VERSION 5.7 ;
BUSBITCHARS "[]" ;
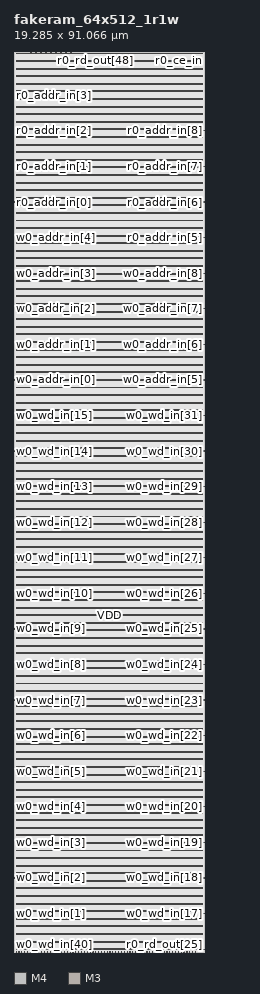
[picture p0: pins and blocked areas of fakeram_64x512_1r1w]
MACRO fakeram_64x512_1r1w
  FOREIGN fakeram_64x512_1r1w 0 0 ;
  SYMMETRY X Y R90 ;
  SIZE 19.285 BY 91.066 ;
  CLASS BLOCK ;
  PIN w0_wd_in[0]
    DIRECTION INPUT ;
    USE SIGNAL ;
    SHAPE ABUTMENT ;
    PORT
      LAYER M4 ;
      RECT 0.000 0.276 0.072 0.300 ;
    END
  END w0_wd_in[0]
  PIN w0_wd_in[1]
    DIRECTION INPUT ;
    USE SIGNAL ;
    SHAPE ABUTMENT ;
    PORT
      LAYER M4 ;
      RECT 0.000 3.876 0.072 3.900 ;
    END
  END w0_wd_in[1]
  PIN w0_wd_in[2]
    DIRECTION INPUT ;
    USE SIGNAL ;
    SHAPE ABUTMENT ;
    PORT
      LAYER M4 ;
      RECT 0.000 7.476 0.072 7.500 ;
    END
  END w0_wd_in[2]
  PIN w0_wd_in[3]
    DIRECTION INPUT ;
    USE SIGNAL ;
    SHAPE ABUTMENT ;
    PORT
      LAYER M4 ;
      RECT 0.000 11.076 0.072 11.100 ;
    END
  END w0_wd_in[3]
  PIN w0_wd_in[4]
    DIRECTION INPUT ;
    USE SIGNAL ;
    SHAPE ABUTMENT ;
    PORT
      LAYER M4 ;
      RECT 0.000 14.676 0.072 14.700 ;
    END
  END w0_wd_in[4]
  PIN w0_wd_in[5]
    DIRECTION INPUT ;
    USE SIGNAL ;
    SHAPE ABUTMENT ;
    PORT
      LAYER M4 ;
      RECT 0.000 18.276 0.072 18.300 ;
    END
  END w0_wd_in[5]
  PIN w0_wd_in[6]
    DIRECTION INPUT ;
    USE SIGNAL ;
    SHAPE ABUTMENT ;
    PORT
      LAYER M4 ;
      RECT 0.000 21.876 0.072 21.900 ;
    END
  END w0_wd_in[6]
  PIN w0_wd_in[7]
    DIRECTION INPUT ;
    USE SIGNAL ;
    SHAPE ABUTMENT ;
    PORT
      LAYER M4 ;
      RECT 0.000 25.476 0.072 25.500 ;
    END
  END w0_wd_in[7]
  PIN w0_wd_in[8]
    DIRECTION INPUT ;
    USE SIGNAL ;
    SHAPE ABUTMENT ;
    PORT
      LAYER M4 ;
      RECT 0.000 29.076 0.072 29.100 ;
    END
  END w0_wd_in[8]
  PIN w0_wd_in[9]
    DIRECTION INPUT ;
    USE SIGNAL ;
    SHAPE ABUTMENT ;
    PORT
      LAYER M4 ;
      RECT 0.000 32.676 0.072 32.700 ;
    END
  END w0_wd_in[9]
  PIN w0_wd_in[10]
    DIRECTION INPUT ;
    USE SIGNAL ;
    SHAPE ABUTMENT ;
    PORT
      LAYER M4 ;
      RECT 0.000 36.276 0.072 36.300 ;
    END
  END w0_wd_in[10]
  PIN w0_wd_in[11]
    DIRECTION INPUT ;
    USE SIGNAL ;
    SHAPE ABUTMENT ;
    PORT
      LAYER M4 ;
      RECT 0.000 39.876 0.072 39.900 ;
    END
  END w0_wd_in[11]
  PIN w0_wd_in[12]
    DIRECTION INPUT ;
    USE SIGNAL ;
    SHAPE ABUTMENT ;
    PORT
      LAYER M4 ;
      RECT 0.000 43.476 0.072 43.500 ;
    END
  END w0_wd_in[12]
  PIN w0_wd_in[13]
    DIRECTION INPUT ;
    USE SIGNAL ;
    SHAPE ABUTMENT ;
    PORT
      LAYER M4 ;
      RECT 0.000 47.076 0.072 47.100 ;
    END
  END w0_wd_in[13]
  PIN w0_wd_in[14]
    DIRECTION INPUT ;
    USE SIGNAL ;
    SHAPE ABUTMENT ;
    PORT
      LAYER M4 ;
      RECT 0.000 50.676 0.072 50.700 ;
    END
  END w0_wd_in[14]
  PIN w0_wd_in[15]
    DIRECTION INPUT ;
    USE SIGNAL ;
    SHAPE ABUTMENT ;
    PORT
      LAYER M4 ;
      RECT 0.000 54.276 0.072 54.300 ;
    END
  END w0_wd_in[15]
  PIN w0_wd_in[16]
    DIRECTION INPUT ;
    USE SIGNAL ;
    SHAPE ABUTMENT ;
    PORT
      LAYER M4 ;
      RECT 19.213 0.276 19.285 0.300 ;
    END
  END w0_wd_in[16]
  PIN w0_wd_in[17]
    DIRECTION INPUT ;
    USE SIGNAL ;
    SHAPE ABUTMENT ;
    PORT
      LAYER M4 ;
      RECT 19.213 3.876 19.285 3.900 ;
    END
  END w0_wd_in[17]
  PIN w0_wd_in[18]
    DIRECTION INPUT ;
    USE SIGNAL ;
    SHAPE ABUTMENT ;
    PORT
      LAYER M4 ;
      RECT 19.213 7.476 19.285 7.500 ;
    END
  END w0_wd_in[18]
  PIN w0_wd_in[19]
    DIRECTION INPUT ;
    USE SIGNAL ;
    SHAPE ABUTMENT ;
    PORT
      LAYER M4 ;
      RECT 19.213 11.076 19.285 11.100 ;
    END
  END w0_wd_in[19]
  PIN w0_wd_in[20]
    DIRECTION INPUT ;
    USE SIGNAL ;
    SHAPE ABUTMENT ;
    PORT
      LAYER M4 ;
      RECT 19.213 14.676 19.285 14.700 ;
    END
  END w0_wd_in[20]
  PIN w0_wd_in[21]
    DIRECTION INPUT ;
    USE SIGNAL ;
    SHAPE ABUTMENT ;
    PORT
      LAYER M4 ;
      RECT 19.213 18.276 19.285 18.300 ;
    END
  END w0_wd_in[21]
  PIN w0_wd_in[22]
    DIRECTION INPUT ;
    USE SIGNAL ;
    SHAPE ABUTMENT ;
    PORT
      LAYER M4 ;
      RECT 19.213 21.876 19.285 21.900 ;
    END
  END w0_wd_in[22]
  PIN w0_wd_in[23]
    DIRECTION INPUT ;
    USE SIGNAL ;
    SHAPE ABUTMENT ;
    PORT
      LAYER M4 ;
      RECT 19.213 25.476 19.285 25.500 ;
    END
  END w0_wd_in[23]
  PIN w0_wd_in[24]
    DIRECTION INPUT ;
    USE SIGNAL ;
    SHAPE ABUTMENT ;
    PORT
      LAYER M4 ;
      RECT 19.213 29.076 19.285 29.100 ;
    END
  END w0_wd_in[24]
  PIN w0_wd_in[25]
    DIRECTION INPUT ;
    USE SIGNAL ;
    SHAPE ABUTMENT ;
    PORT
      LAYER M4 ;
      RECT 19.213 32.676 19.285 32.700 ;
    END
  END w0_wd_in[25]
  PIN w0_wd_in[26]
    DIRECTION INPUT ;
    USE SIGNAL ;
    SHAPE ABUTMENT ;
    PORT
      LAYER M4 ;
      RECT 19.213 36.276 19.285 36.300 ;
    END
  END w0_wd_in[26]
  PIN w0_wd_in[27]
    DIRECTION INPUT ;
    USE SIGNAL ;
    SHAPE ABUTMENT ;
    PORT
      LAYER M4 ;
      RECT 19.213 39.876 19.285 39.900 ;
    END
  END w0_wd_in[27]
  PIN w0_wd_in[28]
    DIRECTION INPUT ;
    USE SIGNAL ;
    SHAPE ABUTMENT ;
    PORT
      LAYER M4 ;
      RECT 19.213 43.476 19.285 43.500 ;
    END
  END w0_wd_in[28]
  PIN w0_wd_in[29]
    DIRECTION INPUT ;
    USE SIGNAL ;
    SHAPE ABUTMENT ;
    PORT
      LAYER M4 ;
      RECT 19.213 47.076 19.285 47.100 ;
    END
  END w0_wd_in[29]
  PIN w0_wd_in[30]
    DIRECTION INPUT ;
    USE SIGNAL ;
    SHAPE ABUTMENT ;
    PORT
      LAYER M4 ;
      RECT 19.213 50.676 19.285 50.700 ;
    END
  END w0_wd_in[30]
  PIN w0_wd_in[31]
    DIRECTION INPUT ;
    USE SIGNAL ;
    SHAPE ABUTMENT ;
    PORT
      LAYER M4 ;
      RECT 19.213 54.276 19.285 54.300 ;
    END
  END w0_wd_in[31]
  PIN w0_wd_in[32]
    DIRECTION OUTPUT ;
    USE SIGNAL ;
    SHAPE ABUTMENT ;
    PORT
      LAYER M3 ;
      RECT 0.207 0.000 0.225 0.054 ;
    END
  END w0_wd_in[32]
  PIN w0_wd_in[33]
    DIRECTION OUTPUT ;
    USE SIGNAL ;
    SHAPE ABUTMENT ;
    PORT
      LAYER M3 ;
      RECT 0.495 0.000 0.513 0.054 ;
    END
  END w0_wd_in[33]
  PIN w0_wd_in[34]
    DIRECTION OUTPUT ;
    USE SIGNAL ;
    SHAPE ABUTMENT ;
    PORT
      LAYER M3 ;
      RECT 0.783 0.000 0.801 0.054 ;
    END
  END w0_wd_in[34]
  PIN w0_wd_in[35]
    DIRECTION OUTPUT ;
    USE SIGNAL ;
    SHAPE ABUTMENT ;
    PORT
      LAYER M3 ;
      RECT 1.071 0.000 1.089 0.054 ;
    END
  END w0_wd_in[35]
  PIN w0_wd_in[36]
    DIRECTION OUTPUT ;
    USE SIGNAL ;
    SHAPE ABUTMENT ;
    PORT
      LAYER M3 ;
      RECT 1.359 0.000 1.377 0.054 ;
    END
  END w0_wd_in[36]
  PIN w0_wd_in[37]
    DIRECTION OUTPUT ;
    USE SIGNAL ;
    SHAPE ABUTMENT ;
    PORT
      LAYER M3 ;
      RECT 1.647 0.000 1.665 0.054 ;
    END
  END w0_wd_in[37]
  PIN w0_wd_in[38]
    DIRECTION OUTPUT ;
    USE SIGNAL ;
    SHAPE ABUTMENT ;
    PORT
      LAYER M3 ;
      RECT 1.935 0.000 1.953 0.054 ;
    END
  END w0_wd_in[38]
  PIN w0_wd_in[39]
    DIRECTION OUTPUT ;
    USE SIGNAL ;
    SHAPE ABUTMENT ;
    PORT
      LAYER M3 ;
      RECT 2.223 0.000 2.241 0.054 ;
    END
  END w0_wd_in[39]
  PIN w0_wd_in[40]
    DIRECTION OUTPUT ;
    USE SIGNAL ;
    SHAPE ABUTMENT ;
    PORT
      LAYER M3 ;
      RECT 2.511 0.000 2.529 0.054 ;
    END
  END w0_wd_in[40]
  PIN w0_wd_in[41]
    DIRECTION OUTPUT ;
    USE SIGNAL ;
    SHAPE ABUTMENT ;
    PORT
      LAYER M3 ;
      RECT 2.799 0.000 2.817 0.054 ;
    END
  END w0_wd_in[41]
  PIN w0_wd_in[42]
    DIRECTION OUTPUT ;
    USE SIGNAL ;
    SHAPE ABUTMENT ;
    PORT
      LAYER M3 ;
      RECT 3.087 0.000 3.105 0.054 ;
    END
  END w0_wd_in[42]
  PIN w0_wd_in[43]
    DIRECTION OUTPUT ;
    USE SIGNAL ;
    SHAPE ABUTMENT ;
    PORT
      LAYER M3 ;
      RECT 3.375 0.000 3.393 0.054 ;
    END
  END w0_wd_in[43]
  PIN w0_wd_in[44]
    DIRECTION OUTPUT ;
    USE SIGNAL ;
    SHAPE ABUTMENT ;
    PORT
      LAYER M3 ;
      RECT 3.663 0.000 3.681 0.054 ;
    END
  END w0_wd_in[44]
  PIN w0_wd_in[45]
    DIRECTION OUTPUT ;
    USE SIGNAL ;
    SHAPE ABUTMENT ;
    PORT
      LAYER M3 ;
      RECT 3.951 0.000 3.969 0.054 ;
    END
  END w0_wd_in[45]
  PIN w0_wd_in[46]
    DIRECTION OUTPUT ;
    USE SIGNAL ;
    SHAPE ABUTMENT ;
    PORT
      LAYER M3 ;
      RECT 4.239 0.000 4.257 0.054 ;
    END
  END w0_wd_in[46]
  PIN w0_wd_in[47]
    DIRECTION OUTPUT ;
    USE SIGNAL ;
    SHAPE ABUTMENT ;
    PORT
      LAYER M3 ;
      RECT 4.527 0.000 4.545 0.054 ;
    END
  END w0_wd_in[47]
  PIN w0_wd_in[48]
    DIRECTION OUTPUT ;
    USE SIGNAL ;
    SHAPE ABUTMENT ;
    PORT
      LAYER M3 ;
      RECT 4.815 0.000 4.833 0.054 ;
    END
  END w0_wd_in[48]
  PIN w0_wd_in[49]
    DIRECTION OUTPUT ;
    USE SIGNAL ;
    SHAPE ABUTMENT ;
    PORT
      LAYER M3 ;
      RECT 5.103 0.000 5.121 0.054 ;
    END
  END w0_wd_in[49]
  PIN w0_wd_in[50]
    DIRECTION OUTPUT ;
    USE SIGNAL ;
    SHAPE ABUTMENT ;
    PORT
      LAYER M3 ;
      RECT 5.391 0.000 5.409 0.054 ;
    END
  END w0_wd_in[50]
  PIN w0_wd_in[51]
    DIRECTION OUTPUT ;
    USE SIGNAL ;
    SHAPE ABUTMENT ;
    PORT
      LAYER M3 ;
      RECT 5.679 0.000 5.697 0.054 ;
    END
  END w0_wd_in[51]
  PIN w0_wd_in[52]
    DIRECTION OUTPUT ;
    USE SIGNAL ;
    SHAPE ABUTMENT ;
    PORT
      LAYER M3 ;
      RECT 5.967 0.000 5.985 0.054 ;
    END
  END w0_wd_in[52]
  PIN w0_wd_in[53]
    DIRECTION OUTPUT ;
    USE SIGNAL ;
    SHAPE ABUTMENT ;
    PORT
      LAYER M3 ;
      RECT 6.255 0.000 6.273 0.054 ;
    END
  END w0_wd_in[53]
  PIN w0_wd_in[54]
    DIRECTION OUTPUT ;
    USE SIGNAL ;
    SHAPE ABUTMENT ;
    PORT
      LAYER M3 ;
      RECT 6.543 0.000 6.561 0.054 ;
    END
  END w0_wd_in[54]
  PIN w0_wd_in[55]
    DIRECTION OUTPUT ;
    USE SIGNAL ;
    SHAPE ABUTMENT ;
    PORT
      LAYER M3 ;
      RECT 6.831 0.000 6.849 0.054 ;
    END
  END w0_wd_in[55]
  PIN w0_wd_in[56]
    DIRECTION OUTPUT ;
    USE SIGNAL ;
    SHAPE ABUTMENT ;
    PORT
      LAYER M3 ;
      RECT 7.119 0.000 7.137 0.054 ;
    END
  END w0_wd_in[56]
  PIN w0_wd_in[57]
    DIRECTION OUTPUT ;
    USE SIGNAL ;
    SHAPE ABUTMENT ;
    PORT
      LAYER M3 ;
      RECT 7.407 0.000 7.425 0.054 ;
    END
  END w0_wd_in[57]
  PIN w0_wd_in[58]
    DIRECTION OUTPUT ;
    USE SIGNAL ;
    SHAPE ABUTMENT ;
    PORT
      LAYER M3 ;
      RECT 7.695 0.000 7.713 0.054 ;
    END
  END w0_wd_in[58]
  PIN w0_wd_in[59]
    DIRECTION OUTPUT ;
    USE SIGNAL ;
    SHAPE ABUTMENT ;
    PORT
      LAYER M3 ;
      RECT 7.983 0.000 8.001 0.054 ;
    END
  END w0_wd_in[59]
  PIN w0_wd_in[60]
    DIRECTION OUTPUT ;
    USE SIGNAL ;
    SHAPE ABUTMENT ;
    PORT
      LAYER M3 ;
      RECT 8.271 0.000 8.289 0.054 ;
    END
  END w0_wd_in[60]
  PIN w0_wd_in[61]
    DIRECTION OUTPUT ;
    USE SIGNAL ;
    SHAPE ABUTMENT ;
    PORT
      LAYER M3 ;
      RECT 8.559 0.000 8.577 0.054 ;
    END
  END w0_wd_in[61]
  PIN w0_wd_in[62]
    DIRECTION OUTPUT ;
    USE SIGNAL ;
    SHAPE ABUTMENT ;
    PORT
      LAYER M3 ;
      RECT 8.847 0.000 8.865 0.054 ;
    END
  END w0_wd_in[62]
  PIN w0_wd_in[63]
    DIRECTION OUTPUT ;
    USE SIGNAL ;
    SHAPE ABUTMENT ;
    PORT
      LAYER M3 ;
      RECT 9.135 0.000 9.153 0.054 ;
    END
  END w0_wd_in[63]
  PIN r0_rd_out[0]
    DIRECTION OUTPUT ;
    USE SIGNAL ;
    SHAPE ABUTMENT ;
    PORT
      LAYER M3 ;
      RECT 9.423 0.000 9.441 0.054 ;
    END
  END r0_rd_out[0]
  PIN r0_rd_out[1]
    DIRECTION OUTPUT ;
    USE SIGNAL ;
    SHAPE ABUTMENT ;
    PORT
      LAYER M3 ;
      RECT 9.711 0.000 9.729 0.054 ;
    END
  END r0_rd_out[1]
  PIN r0_rd_out[2]
    DIRECTION OUTPUT ;
    USE SIGNAL ;
    SHAPE ABUTMENT ;
    PORT
      LAYER M3 ;
      RECT 9.999 0.000 10.017 0.054 ;
    END
  END r0_rd_out[2]
  PIN r0_rd_out[3]
    DIRECTION OUTPUT ;
    USE SIGNAL ;
    SHAPE ABUTMENT ;
    PORT
      LAYER M3 ;
      RECT 10.287 0.000 10.305 0.054 ;
    END
  END r0_rd_out[3]
  PIN r0_rd_out[4]
    DIRECTION OUTPUT ;
    USE SIGNAL ;
    SHAPE ABUTMENT ;
    PORT
      LAYER M3 ;
      RECT 10.575 0.000 10.593 0.054 ;
    END
  END r0_rd_out[4]
  PIN r0_rd_out[5]
    DIRECTION OUTPUT ;
    USE SIGNAL ;
    SHAPE ABUTMENT ;
    PORT
      LAYER M3 ;
      RECT 10.863 0.000 10.881 0.054 ;
    END
  END r0_rd_out[5]
  PIN r0_rd_out[6]
    DIRECTION OUTPUT ;
    USE SIGNAL ;
    SHAPE ABUTMENT ;
    PORT
      LAYER M3 ;
      RECT 11.151 0.000 11.169 0.054 ;
    END
  END r0_rd_out[6]
  PIN r0_rd_out[7]
    DIRECTION OUTPUT ;
    USE SIGNAL ;
    SHAPE ABUTMENT ;
    PORT
      LAYER M3 ;
      RECT 11.439 0.000 11.457 0.054 ;
    END
  END r0_rd_out[7]
  PIN r0_rd_out[8]
    DIRECTION OUTPUT ;
    USE SIGNAL ;
    SHAPE ABUTMENT ;
    PORT
      LAYER M3 ;
      RECT 11.727 0.000 11.745 0.054 ;
    END
  END r0_rd_out[8]
  PIN r0_rd_out[9]
    DIRECTION OUTPUT ;
    USE SIGNAL ;
    SHAPE ABUTMENT ;
    PORT
      LAYER M3 ;
      RECT 12.015 0.000 12.033 0.054 ;
    END
  END r0_rd_out[9]
  PIN r0_rd_out[10]
    DIRECTION OUTPUT ;
    USE SIGNAL ;
    SHAPE ABUTMENT ;
    PORT
      LAYER M3 ;
      RECT 12.303 0.000 12.321 0.054 ;
    END
  END r0_rd_out[10]
  PIN r0_rd_out[11]
    DIRECTION OUTPUT ;
    USE SIGNAL ;
    SHAPE ABUTMENT ;
    PORT
      LAYER M3 ;
      RECT 12.591 0.000 12.609 0.054 ;
    END
  END r0_rd_out[11]
  PIN r0_rd_out[12]
    DIRECTION OUTPUT ;
    USE SIGNAL ;
    SHAPE ABUTMENT ;
    PORT
      LAYER M3 ;
      RECT 12.879 0.000 12.897 0.054 ;
    END
  END r0_rd_out[12]
  PIN r0_rd_out[13]
    DIRECTION OUTPUT ;
    USE SIGNAL ;
    SHAPE ABUTMENT ;
    PORT
      LAYER M3 ;
      RECT 13.167 0.000 13.185 0.054 ;
    END
  END r0_rd_out[13]
  PIN r0_rd_out[14]
    DIRECTION OUTPUT ;
    USE SIGNAL ;
    SHAPE ABUTMENT ;
    PORT
      LAYER M3 ;
      RECT 13.455 0.000 13.473 0.054 ;
    END
  END r0_rd_out[14]
  PIN r0_rd_out[15]
    DIRECTION OUTPUT ;
    USE SIGNAL ;
    SHAPE ABUTMENT ;
    PORT
      LAYER M3 ;
      RECT 13.743 0.000 13.761 0.054 ;
    END
  END r0_rd_out[15]
  PIN r0_rd_out[16]
    DIRECTION OUTPUT ;
    USE SIGNAL ;
    SHAPE ABUTMENT ;
    PORT
      LAYER M3 ;
      RECT 14.031 0.000 14.049 0.054 ;
    END
  END r0_rd_out[16]
  PIN r0_rd_out[17]
    DIRECTION OUTPUT ;
    USE SIGNAL ;
    SHAPE ABUTMENT ;
    PORT
      LAYER M3 ;
      RECT 14.319 0.000 14.337 0.054 ;
    END
  END r0_rd_out[17]
  PIN r0_rd_out[18]
    DIRECTION OUTPUT ;
    USE SIGNAL ;
    SHAPE ABUTMENT ;
    PORT
      LAYER M3 ;
      RECT 14.607 0.000 14.625 0.054 ;
    END
  END r0_rd_out[18]
  PIN r0_rd_out[19]
    DIRECTION OUTPUT ;
    USE SIGNAL ;
    SHAPE ABUTMENT ;
    PORT
      LAYER M3 ;
      RECT 14.895 0.000 14.913 0.054 ;
    END
  END r0_rd_out[19]
  PIN r0_rd_out[20]
    DIRECTION OUTPUT ;
    USE SIGNAL ;
    SHAPE ABUTMENT ;
    PORT
      LAYER M3 ;
      RECT 15.183 0.000 15.201 0.054 ;
    END
  END r0_rd_out[20]
  PIN r0_rd_out[21]
    DIRECTION OUTPUT ;
    USE SIGNAL ;
    SHAPE ABUTMENT ;
    PORT
      LAYER M3 ;
      RECT 15.471 0.000 15.489 0.054 ;
    END
  END r0_rd_out[21]
  PIN r0_rd_out[22]
    DIRECTION OUTPUT ;
    USE SIGNAL ;
    SHAPE ABUTMENT ;
    PORT
      LAYER M3 ;
      RECT 15.759 0.000 15.777 0.054 ;
    END
  END r0_rd_out[22]
  PIN r0_rd_out[23]
    DIRECTION OUTPUT ;
    USE SIGNAL ;
    SHAPE ABUTMENT ;
    PORT
      LAYER M3 ;
      RECT 16.047 0.000 16.065 0.054 ;
    END
  END r0_rd_out[23]
  PIN r0_rd_out[24]
    DIRECTION OUTPUT ;
    USE SIGNAL ;
    SHAPE ABUTMENT ;
    PORT
      LAYER M3 ;
      RECT 16.335 0.000 16.353 0.054 ;
    END
  END r0_rd_out[24]
  PIN r0_rd_out[25]
    DIRECTION OUTPUT ;
    USE SIGNAL ;
    SHAPE ABUTMENT ;
    PORT
      LAYER M3 ;
      RECT 16.623 0.000 16.641 0.054 ;
    END
  END r0_rd_out[25]
  PIN r0_rd_out[26]
    DIRECTION OUTPUT ;
    USE SIGNAL ;
    SHAPE ABUTMENT ;
    PORT
      LAYER M3 ;
      RECT 16.911 0.000 16.929 0.054 ;
    END
  END r0_rd_out[26]
  PIN r0_rd_out[27]
    DIRECTION OUTPUT ;
    USE SIGNAL ;
    SHAPE ABUTMENT ;
    PORT
      LAYER M3 ;
      RECT 17.199 0.000 17.217 0.054 ;
    END
  END r0_rd_out[27]
  PIN r0_rd_out[28]
    DIRECTION OUTPUT ;
    USE SIGNAL ;
    SHAPE ABUTMENT ;
    PORT
      LAYER M3 ;
      RECT 17.487 0.000 17.505 0.054 ;
    END
  END r0_rd_out[28]
  PIN r0_rd_out[29]
    DIRECTION OUTPUT ;
    USE SIGNAL ;
    SHAPE ABUTMENT ;
    PORT
      LAYER M3 ;
      RECT 17.775 0.000 17.793 0.054 ;
    END
  END r0_rd_out[29]
  PIN r0_rd_out[30]
    DIRECTION OUTPUT ;
    USE SIGNAL ;
    SHAPE ABUTMENT ;
    PORT
      LAYER M3 ;
      RECT 18.063 0.000 18.081 0.054 ;
    END
  END r0_rd_out[30]
  PIN r0_rd_out[31]
    DIRECTION OUTPUT ;
    USE SIGNAL ;
    SHAPE ABUTMENT ;
    PORT
      LAYER M3 ;
      RECT 18.351 0.000 18.369 0.054 ;
    END
  END r0_rd_out[31]
  PIN r0_rd_out[32]
    DIRECTION OUTPUT ;
    USE SIGNAL ;
    SHAPE ABUTMENT ;
    PORT
      LAYER M3 ;
      RECT 0.207 91.012 0.225 91.066 ;
    END
  END r0_rd_out[32]
  PIN r0_rd_out[33]
    DIRECTION OUTPUT ;
    USE SIGNAL ;
    SHAPE ABUTMENT ;
    PORT
      LAYER M3 ;
      RECT 0.711 91.012 0.729 91.066 ;
    END
  END r0_rd_out[33]
  PIN r0_rd_out[34]
    DIRECTION OUTPUT ;
    USE SIGNAL ;
    SHAPE ABUTMENT ;
    PORT
      LAYER M3 ;
      RECT 1.215 91.012 1.233 91.066 ;
    END
  END r0_rd_out[34]
  PIN r0_rd_out[35]
    DIRECTION OUTPUT ;
    USE SIGNAL ;
    SHAPE ABUTMENT ;
    PORT
      LAYER M3 ;
      RECT 1.719 91.012 1.737 91.066 ;
    END
  END r0_rd_out[35]
  PIN r0_rd_out[36]
    DIRECTION OUTPUT ;
    USE SIGNAL ;
    SHAPE ABUTMENT ;
    PORT
      LAYER M3 ;
      RECT 2.223 91.012 2.241 91.066 ;
    END
  END r0_rd_out[36]
  PIN r0_rd_out[37]
    DIRECTION OUTPUT ;
    USE SIGNAL ;
    SHAPE ABUTMENT ;
    PORT
      LAYER M3 ;
      RECT 2.727 91.012 2.745 91.066 ;
    END
  END r0_rd_out[37]
  PIN r0_rd_out[38]
    DIRECTION OUTPUT ;
    USE SIGNAL ;
    SHAPE ABUTMENT ;
    PORT
      LAYER M3 ;
      RECT 3.231 91.012 3.249 91.066 ;
    END
  END r0_rd_out[38]
  PIN r0_rd_out[39]
    DIRECTION OUTPUT ;
    USE SIGNAL ;
    SHAPE ABUTMENT ;
    PORT
      LAYER M3 ;
      RECT 3.735 91.012 3.753 91.066 ;
    END
  END r0_rd_out[39]
  PIN r0_rd_out[40]
    DIRECTION OUTPUT ;
    USE SIGNAL ;
    SHAPE ABUTMENT ;
    PORT
      LAYER M3 ;
      RECT 4.239 91.012 4.257 91.066 ;
    END
  END r0_rd_out[40]
  PIN r0_rd_out[41]
    DIRECTION OUTPUT ;
    USE SIGNAL ;
    SHAPE ABUTMENT ;
    PORT
      LAYER M3 ;
      RECT 4.743 91.012 4.761 91.066 ;
    END
  END r0_rd_out[41]
  PIN r0_rd_out[42]
    DIRECTION OUTPUT ;
    USE SIGNAL ;
    SHAPE ABUTMENT ;
    PORT
      LAYER M3 ;
      RECT 5.247 91.012 5.265 91.066 ;
    END
  END r0_rd_out[42]
  PIN r0_rd_out[43]
    DIRECTION OUTPUT ;
    USE SIGNAL ;
    SHAPE ABUTMENT ;
    PORT
      LAYER M3 ;
      RECT 5.751 91.012 5.769 91.066 ;
    END
  END r0_rd_out[43]
  PIN r0_rd_out[44]
    DIRECTION OUTPUT ;
    USE SIGNAL ;
    SHAPE ABUTMENT ;
    PORT
      LAYER M3 ;
      RECT 6.255 91.012 6.273 91.066 ;
    END
  END r0_rd_out[44]
  PIN r0_rd_out[45]
    DIRECTION OUTPUT ;
    USE SIGNAL ;
    SHAPE ABUTMENT ;
    PORT
      LAYER M3 ;
      RECT 6.759 91.012 6.777 91.066 ;
    END
  END r0_rd_out[45]
  PIN r0_rd_out[46]
    DIRECTION OUTPUT ;
    USE SIGNAL ;
    SHAPE ABUTMENT ;
    PORT
      LAYER M3 ;
      RECT 7.263 91.012 7.281 91.066 ;
    END
  END r0_rd_out[46]
  PIN r0_rd_out[47]
    DIRECTION OUTPUT ;
    USE SIGNAL ;
    SHAPE ABUTMENT ;
    PORT
      LAYER M3 ;
      RECT 7.767 91.012 7.785 91.066 ;
    END
  END r0_rd_out[47]
  PIN r0_rd_out[48]
    DIRECTION OUTPUT ;
    USE SIGNAL ;
    SHAPE ABUTMENT ;
    PORT
      LAYER M3 ;
      RECT 8.271 91.012 8.289 91.066 ;
    END
  END r0_rd_out[48]
  PIN r0_rd_out[49]
    DIRECTION OUTPUT ;
    USE SIGNAL ;
    SHAPE ABUTMENT ;
    PORT
      LAYER M3 ;
      RECT 8.775 91.012 8.793 91.066 ;
    END
  END r0_rd_out[49]
  PIN r0_rd_out[50]
    DIRECTION OUTPUT ;
    USE SIGNAL ;
    SHAPE ABUTMENT ;
    PORT
      LAYER M3 ;
      RECT 9.279 91.012 9.297 91.066 ;
    END
  END r0_rd_out[50]
  PIN r0_rd_out[51]
    DIRECTION OUTPUT ;
    USE SIGNAL ;
    SHAPE ABUTMENT ;
    PORT
      LAYER M3 ;
      RECT 9.783 91.012 9.801 91.066 ;
    END
  END r0_rd_out[51]
  PIN r0_rd_out[52]
    DIRECTION OUTPUT ;
    USE SIGNAL ;
    SHAPE ABUTMENT ;
    PORT
      LAYER M3 ;
      RECT 10.287 91.012 10.305 91.066 ;
    END
  END r0_rd_out[52]
  PIN r0_rd_out[53]
    DIRECTION OUTPUT ;
    USE SIGNAL ;
    SHAPE ABUTMENT ;
    PORT
      LAYER M3 ;
      RECT 10.791 91.012 10.809 91.066 ;
    END
  END r0_rd_out[53]
  PIN r0_rd_out[54]
    DIRECTION OUTPUT ;
    USE SIGNAL ;
    SHAPE ABUTMENT ;
    PORT
      LAYER M3 ;
      RECT 11.295 91.012 11.313 91.066 ;
    END
  END r0_rd_out[54]
  PIN r0_rd_out[55]
    DIRECTION OUTPUT ;
    USE SIGNAL ;
    SHAPE ABUTMENT ;
    PORT
      LAYER M3 ;
      RECT 11.799 91.012 11.817 91.066 ;
    END
  END r0_rd_out[55]
  PIN r0_rd_out[56]
    DIRECTION OUTPUT ;
    USE SIGNAL ;
    SHAPE ABUTMENT ;
    PORT
      LAYER M3 ;
      RECT 12.303 91.012 12.321 91.066 ;
    END
  END r0_rd_out[56]
  PIN r0_rd_out[57]
    DIRECTION OUTPUT ;
    USE SIGNAL ;
    SHAPE ABUTMENT ;
    PORT
      LAYER M3 ;
      RECT 12.807 91.012 12.825 91.066 ;
    END
  END r0_rd_out[57]
  PIN r0_rd_out[58]
    DIRECTION OUTPUT ;
    USE SIGNAL ;
    SHAPE ABUTMENT ;
    PORT
      LAYER M3 ;
      RECT 13.311 91.012 13.329 91.066 ;
    END
  END r0_rd_out[58]
  PIN r0_rd_out[59]
    DIRECTION OUTPUT ;
    USE SIGNAL ;
    SHAPE ABUTMENT ;
    PORT
      LAYER M3 ;
      RECT 13.815 91.012 13.833 91.066 ;
    END
  END r0_rd_out[59]
  PIN r0_rd_out[60]
    DIRECTION OUTPUT ;
    USE SIGNAL ;
    SHAPE ABUTMENT ;
    PORT
      LAYER M3 ;
      RECT 14.319 91.012 14.337 91.066 ;
    END
  END r0_rd_out[60]
  PIN r0_rd_out[61]
    DIRECTION OUTPUT ;
    USE SIGNAL ;
    SHAPE ABUTMENT ;
    PORT
      LAYER M3 ;
      RECT 14.823 91.012 14.841 91.066 ;
    END
  END r0_rd_out[61]
  PIN r0_rd_out[62]
    DIRECTION OUTPUT ;
    USE SIGNAL ;
    SHAPE ABUTMENT ;
    PORT
      LAYER M3 ;
      RECT 15.327 91.012 15.345 91.066 ;
    END
  END r0_rd_out[62]
  PIN r0_rd_out[63]
    DIRECTION OUTPUT ;
    USE SIGNAL ;
    SHAPE ABUTMENT ;
    PORT
      LAYER M3 ;
      RECT 15.831 91.012 15.849 91.066 ;
    END
  END r0_rd_out[63]
  PIN w0_addr_in[0]
    DIRECTION INPUT ;
    USE SIGNAL ;
    SHAPE ABUTMENT ;
    PORT
      LAYER M4 ;
      RECT 0.000 57.876 0.072 57.900 ;
    END
  END w0_addr_in[0]
  PIN w0_addr_in[1]
    DIRECTION INPUT ;
    USE SIGNAL ;
    SHAPE ABUTMENT ;
    PORT
      LAYER M4 ;
      RECT 0.000 61.476 0.072 61.500 ;
    END
  END w0_addr_in[1]
  PIN w0_addr_in[2]
    DIRECTION INPUT ;
    USE SIGNAL ;
    SHAPE ABUTMENT ;
    PORT
      LAYER M4 ;
      RECT 0.000 65.076 0.072 65.100 ;
    END
  END w0_addr_in[2]
  PIN w0_addr_in[3]
    DIRECTION INPUT ;
    USE SIGNAL ;
    SHAPE ABUTMENT ;
    PORT
      LAYER M4 ;
      RECT 0.000 68.676 0.072 68.700 ;
    END
  END w0_addr_in[3]
  PIN w0_addr_in[4]
    DIRECTION INPUT ;
    USE SIGNAL ;
    SHAPE ABUTMENT ;
    PORT
      LAYER M4 ;
      RECT 0.000 72.276 0.072 72.300 ;
    END
  END w0_addr_in[4]
  PIN w0_addr_in[5]
    DIRECTION INPUT ;
    USE SIGNAL ;
    SHAPE ABUTMENT ;
    PORT
      LAYER M4 ;
      RECT 19.213 57.876 19.285 57.900 ;
    END
  END w0_addr_in[5]
  PIN w0_addr_in[6]
    DIRECTION INPUT ;
    USE SIGNAL ;
    SHAPE ABUTMENT ;
    PORT
      LAYER M4 ;
      RECT 19.213 61.476 19.285 61.500 ;
    END
  END w0_addr_in[6]
  PIN w0_addr_in[7]
    DIRECTION INPUT ;
    USE SIGNAL ;
    SHAPE ABUTMENT ;
    PORT
      LAYER M4 ;
      RECT 19.213 65.076 19.285 65.100 ;
    END
  END w0_addr_in[7]
  PIN w0_addr_in[8]
    DIRECTION INPUT ;
    USE SIGNAL ;
    SHAPE ABUTMENT ;
    PORT
      LAYER M4 ;
      RECT 19.213 68.676 19.285 68.700 ;
    END
  END w0_addr_in[8]
  PIN r0_addr_in[0]
    DIRECTION INPUT ;
    USE SIGNAL ;
    SHAPE ABUTMENT ;
    PORT
      LAYER M4 ;
      RECT 0.000 75.876 0.072 75.900 ;
    END
  END r0_addr_in[0]
  PIN r0_addr_in[1]
    DIRECTION INPUT ;
    USE SIGNAL ;
    SHAPE ABUTMENT ;
    PORT
      LAYER M4 ;
      RECT 0.000 79.476 0.072 79.500 ;
    END
  END r0_addr_in[1]
  PIN r0_addr_in[2]
    DIRECTION INPUT ;
    USE SIGNAL ;
    SHAPE ABUTMENT ;
    PORT
      LAYER M4 ;
      RECT 0.000 83.076 0.072 83.100 ;
    END
  END r0_addr_in[2]
  PIN r0_addr_in[3]
    DIRECTION INPUT ;
    USE SIGNAL ;
    SHAPE ABUTMENT ;
    PORT
      LAYER M4 ;
      RECT 0.000 86.676 0.072 86.700 ;
    END
  END r0_addr_in[3]
  PIN r0_addr_in[4]
    DIRECTION INPUT ;
    USE SIGNAL ;
    SHAPE ABUTMENT ;
    PORT
      LAYER M4 ;
      RECT 0.000 90.276 0.072 90.300 ;
    END
  END r0_addr_in[4]
  PIN r0_addr_in[5]
    DIRECTION INPUT ;
    USE SIGNAL ;
    SHAPE ABUTMENT ;
    PORT
      LAYER M4 ;
      RECT 19.213 72.276 19.285 72.300 ;
    END
  END r0_addr_in[5]
  PIN r0_addr_in[6]
    DIRECTION INPUT ;
    USE SIGNAL ;
    SHAPE ABUTMENT ;
    PORT
      LAYER M4 ;
      RECT 19.213 75.876 19.285 75.900 ;
    END
  END r0_addr_in[6]
  PIN r0_addr_in[7]
    DIRECTION INPUT ;
    USE SIGNAL ;
    SHAPE ABUTMENT ;
    PORT
      LAYER M4 ;
      RECT 19.213 79.476 19.285 79.500 ;
    END
  END r0_addr_in[7]
  PIN r0_addr_in[8]
    DIRECTION INPUT ;
    USE SIGNAL ;
    SHAPE ABUTMENT ;
    PORT
      LAYER M4 ;
      RECT 19.213 83.076 19.285 83.100 ;
    END
  END r0_addr_in[8]
  PIN w0_we_in
    DIRECTION INPUT ;
    USE SIGNAL ;
    SHAPE ABUTMENT ;
    PORT
      LAYER M3 ;
      RECT 16.335 91.012 16.353 91.066 ;
    END
  END w0_we_in
  PIN w0_ce_in
    DIRECTION INPUT ;
    USE SIGNAL ;
    SHAPE ABUTMENT ;
    PORT
      LAYER M3 ;
      RECT 16.839 91.012 16.857 91.066 ;
    END
  END w0_ce_in
  PIN w0_clk
    DIRECTION INPUT ;
    USE SIGNAL ;
    SHAPE ABUTMENT ;
    PORT
      LAYER M3 ;
      RECT 17.343 91.012 17.361 91.066 ;
    END
  END w0_clk
  PIN r0_ce_in
    DIRECTION INPUT ;
    USE SIGNAL ;
    SHAPE ABUTMENT ;
    PORT
      LAYER M3 ;
      RECT 17.847 91.012 17.865 91.066 ;
    END
  END r0_ce_in
  PIN r0_clk
    DIRECTION INPUT ;
    USE SIGNAL ;
    SHAPE ABUTMENT ;
    PORT
      LAYER M3 ;
      RECT 18.351 91.012 18.369 91.066 ;
    END
  END r0_clk
  PIN VSS
    DIRECTION INOUT ;
    USE GROUND ;
    PORT
      LAYER M4 ;
      RECT 0.216 0.240 19.069 0.336 ;
      RECT 0.216 1.008 19.069 1.104 ;
      RECT 0.216 1.776 19.069 1.872 ;
      RECT 0.216 2.544 19.069 2.640 ;
      RECT 0.216 3.312 19.069 3.408 ;
      RECT 0.216 4.080 19.069 4.176 ;
      RECT 0.216 4.848 19.069 4.944 ;
      RECT 0.216 5.616 19.069 5.712 ;
      RECT 0.216 6.384 19.069 6.480 ;
      RECT 0.216 7.152 19.069 7.248 ;
      RECT 0.216 7.920 19.069 8.016 ;
      RECT 0.216 8.688 19.069 8.784 ;
      RECT 0.216 9.456 19.069 9.552 ;
      RECT 0.216 10.224 19.069 10.320 ;
      RECT 0.216 10.992 19.069 11.088 ;
      RECT 0.216 11.760 19.069 11.856 ;
      RECT 0.216 12.528 19.069 12.624 ;
      RECT 0.216 13.296 19.069 13.392 ;
      RECT 0.216 14.064 19.069 14.160 ;
      RECT 0.216 14.832 19.069 14.928 ;
      RECT 0.216 15.600 19.069 15.696 ;
      RECT 0.216 16.368 19.069 16.464 ;
      RECT 0.216 17.136 19.069 17.232 ;
      RECT 0.216 17.904 19.069 18.000 ;
      RECT 0.216 18.672 19.069 18.768 ;
      RECT 0.216 19.440 19.069 19.536 ;
      RECT 0.216 20.208 19.069 20.304 ;
      RECT 0.216 20.976 19.069 21.072 ;
      RECT 0.216 21.744 19.069 21.840 ;
      RECT 0.216 22.512 19.069 22.608 ;
      RECT 0.216 23.280 19.069 23.376 ;
      RECT 0.216 24.048 19.069 24.144 ;
      RECT 0.216 24.816 19.069 24.912 ;
      RECT 0.216 25.584 19.069 25.680 ;
      RECT 0.216 26.352 19.069 26.448 ;
      RECT 0.216 27.120 19.069 27.216 ;
      RECT 0.216 27.888 19.069 27.984 ;
      RECT 0.216 28.656 19.069 28.752 ;
      RECT 0.216 29.424 19.069 29.520 ;
      RECT 0.216 30.192 19.069 30.288 ;
      RECT 0.216 30.960 19.069 31.056 ;
      RECT 0.216 31.728 19.069 31.824 ;
      RECT 0.216 32.496 19.069 32.592 ;
      RECT 0.216 33.264 19.069 33.360 ;
      RECT 0.216 34.032 19.069 34.128 ;
      RECT 0.216 34.800 19.069 34.896 ;
      RECT 0.216 35.568 19.069 35.664 ;
      RECT 0.216 36.336 19.069 36.432 ;
      RECT 0.216 37.104 19.069 37.200 ;
      RECT 0.216 37.872 19.069 37.968 ;
      RECT 0.216 38.640 19.069 38.736 ;
      RECT 0.216 39.408 19.069 39.504 ;
      RECT 0.216 40.176 19.069 40.272 ;
      RECT 0.216 40.944 19.069 41.040 ;
      RECT 0.216 41.712 19.069 41.808 ;
      RECT 0.216 42.480 19.069 42.576 ;
      RECT 0.216 43.248 19.069 43.344 ;
      RECT 0.216 44.016 19.069 44.112 ;
      RECT 0.216 44.784 19.069 44.880 ;
      RECT 0.216 45.552 19.069 45.648 ;
      RECT 0.216 46.320 19.069 46.416 ;
      RECT 0.216 47.088 19.069 47.184 ;
      RECT 0.216 47.856 19.069 47.952 ;
      RECT 0.216 48.624 19.069 48.720 ;
      RECT 0.216 49.392 19.069 49.488 ;
      RECT 0.216 50.160 19.069 50.256 ;
      RECT 0.216 50.928 19.069 51.024 ;
      RECT 0.216 51.696 19.069 51.792 ;
      RECT 0.216 52.464 19.069 52.560 ;
      RECT 0.216 53.232 19.069 53.328 ;
      RECT 0.216 54.000 19.069 54.096 ;
      RECT 0.216 54.768 19.069 54.864 ;
      RECT 0.216 55.536 19.069 55.632 ;
      RECT 0.216 56.304 19.069 56.400 ;
      RECT 0.216 57.072 19.069 57.168 ;
      RECT 0.216 57.840 19.069 57.936 ;
      RECT 0.216 58.608 19.069 58.704 ;
      RECT 0.216 59.376 19.069 59.472 ;
      RECT 0.216 60.144 19.069 60.240 ;
      RECT 0.216 60.912 19.069 61.008 ;
      RECT 0.216 61.680 19.069 61.776 ;
      RECT 0.216 62.448 19.069 62.544 ;
      RECT 0.216 63.216 19.069 63.312 ;
      RECT 0.216 63.984 19.069 64.080 ;
      RECT 0.216 64.752 19.069 64.848 ;
      RECT 0.216 65.520 19.069 65.616 ;
      RECT 0.216 66.288 19.069 66.384 ;
      RECT 0.216 67.056 19.069 67.152 ;
      RECT 0.216 67.824 19.069 67.920 ;
      RECT 0.216 68.592 19.069 68.688 ;
      RECT 0.216 69.360 19.069 69.456 ;
      RECT 0.216 70.128 19.069 70.224 ;
      RECT 0.216 70.896 19.069 70.992 ;
      RECT 0.216 71.664 19.069 71.760 ;
      RECT 0.216 72.432 19.069 72.528 ;
      RECT 0.216 73.200 19.069 73.296 ;
      RECT 0.216 73.968 19.069 74.064 ;
      RECT 0.216 74.736 19.069 74.832 ;
      RECT 0.216 75.504 19.069 75.600 ;
      RECT 0.216 76.272 19.069 76.368 ;
      RECT 0.216 77.040 19.069 77.136 ;
      RECT 0.216 77.808 19.069 77.904 ;
      RECT 0.216 78.576 19.069 78.672 ;
      RECT 0.216 79.344 19.069 79.440 ;
      RECT 0.216 80.112 19.069 80.208 ;
      RECT 0.216 80.880 19.069 80.976 ;
      RECT 0.216 81.648 19.069 81.744 ;
      RECT 0.216 82.416 19.069 82.512 ;
      RECT 0.216 83.184 19.069 83.280 ;
      RECT 0.216 83.952 19.069 84.048 ;
      RECT 0.216 84.720 19.069 84.816 ;
      RECT 0.216 85.488 19.069 85.584 ;
      RECT 0.216 86.256 19.069 86.352 ;
      RECT 0.216 87.024 19.069 87.120 ;
      RECT 0.216 87.792 19.069 87.888 ;
      RECT 0.216 88.560 19.069 88.656 ;
      RECT 0.216 89.328 19.069 89.424 ;
      RECT 0.216 90.096 19.069 90.192 ;
      RECT 0.216 90.864 19.069 90.960 ;
    END
  END VSS
  PIN VDD
    DIRECTION INOUT ;
    USE POWER ;
    PORT
      LAYER M4 ;
      RECT 0.216 0.240 19.069 0.336 ;
      RECT 0.216 1.008 19.069 1.104 ;
      RECT 0.216 1.776 19.069 1.872 ;
      RECT 0.216 2.544 19.069 2.640 ;
      RECT 0.216 3.312 19.069 3.408 ;
      RECT 0.216 4.080 19.069 4.176 ;
      RECT 0.216 4.848 19.069 4.944 ;
      RECT 0.216 5.616 19.069 5.712 ;
      RECT 0.216 6.384 19.069 6.480 ;
      RECT 0.216 7.152 19.069 7.248 ;
      RECT 0.216 7.920 19.069 8.016 ;
      RECT 0.216 8.688 19.069 8.784 ;
      RECT 0.216 9.456 19.069 9.552 ;
      RECT 0.216 10.224 19.069 10.320 ;
      RECT 0.216 10.992 19.069 11.088 ;
      RECT 0.216 11.760 19.069 11.856 ;
      RECT 0.216 12.528 19.069 12.624 ;
      RECT 0.216 13.296 19.069 13.392 ;
      RECT 0.216 14.064 19.069 14.160 ;
      RECT 0.216 14.832 19.069 14.928 ;
      RECT 0.216 15.600 19.069 15.696 ;
      RECT 0.216 16.368 19.069 16.464 ;
      RECT 0.216 17.136 19.069 17.232 ;
      RECT 0.216 17.904 19.069 18.000 ;
      RECT 0.216 18.672 19.069 18.768 ;
      RECT 0.216 19.440 19.069 19.536 ;
      RECT 0.216 20.208 19.069 20.304 ;
      RECT 0.216 20.976 19.069 21.072 ;
      RECT 0.216 21.744 19.069 21.840 ;
      RECT 0.216 22.512 19.069 22.608 ;
      RECT 0.216 23.280 19.069 23.376 ;
      RECT 0.216 24.048 19.069 24.144 ;
      RECT 0.216 24.816 19.069 24.912 ;
      RECT 0.216 25.584 19.069 25.680 ;
      RECT 0.216 26.352 19.069 26.448 ;
      RECT 0.216 27.120 19.069 27.216 ;
      RECT 0.216 27.888 19.069 27.984 ;
      RECT 0.216 28.656 19.069 28.752 ;
      RECT 0.216 29.424 19.069 29.520 ;
      RECT 0.216 30.192 19.069 30.288 ;
      RECT 0.216 30.960 19.069 31.056 ;
      RECT 0.216 31.728 19.069 31.824 ;
      RECT 0.216 32.496 19.069 32.592 ;
      RECT 0.216 33.264 19.069 33.360 ;
      RECT 0.216 34.032 19.069 34.128 ;
      RECT 0.216 34.800 19.069 34.896 ;
      RECT 0.216 35.568 19.069 35.664 ;
      RECT 0.216 36.336 19.069 36.432 ;
      RECT 0.216 37.104 19.069 37.200 ;
      RECT 0.216 37.872 19.069 37.968 ;
      RECT 0.216 38.640 19.069 38.736 ;
      RECT 0.216 39.408 19.069 39.504 ;
      RECT 0.216 40.176 19.069 40.272 ;
      RECT 0.216 40.944 19.069 41.040 ;
      RECT 0.216 41.712 19.069 41.808 ;
      RECT 0.216 42.480 19.069 42.576 ;
      RECT 0.216 43.248 19.069 43.344 ;
      RECT 0.216 44.016 19.069 44.112 ;
      RECT 0.216 44.784 19.069 44.880 ;
      RECT 0.216 45.552 19.069 45.648 ;
      RECT 0.216 46.320 19.069 46.416 ;
      RECT 0.216 47.088 19.069 47.184 ;
      RECT 0.216 47.856 19.069 47.952 ;
      RECT 0.216 48.624 19.069 48.720 ;
      RECT 0.216 49.392 19.069 49.488 ;
      RECT 0.216 50.160 19.069 50.256 ;
      RECT 0.216 50.928 19.069 51.024 ;
      RECT 0.216 51.696 19.069 51.792 ;
      RECT 0.216 52.464 19.069 52.560 ;
      RECT 0.216 53.232 19.069 53.328 ;
      RECT 0.216 54.000 19.069 54.096 ;
      RECT 0.216 54.768 19.069 54.864 ;
      RECT 0.216 55.536 19.069 55.632 ;
      RECT 0.216 56.304 19.069 56.400 ;
      RECT 0.216 57.072 19.069 57.168 ;
      RECT 0.216 57.840 19.069 57.936 ;
      RECT 0.216 58.608 19.069 58.704 ;
      RECT 0.216 59.376 19.069 59.472 ;
      RECT 0.216 60.144 19.069 60.240 ;
      RECT 0.216 60.912 19.069 61.008 ;
      RECT 0.216 61.680 19.069 61.776 ;
      RECT 0.216 62.448 19.069 62.544 ;
      RECT 0.216 63.216 19.069 63.312 ;
      RECT 0.216 63.984 19.069 64.080 ;
      RECT 0.216 64.752 19.069 64.848 ;
      RECT 0.216 65.520 19.069 65.616 ;
      RECT 0.216 66.288 19.069 66.384 ;
      RECT 0.216 67.056 19.069 67.152 ;
      RECT 0.216 67.824 19.069 67.920 ;
      RECT 0.216 68.592 19.069 68.688 ;
      RECT 0.216 69.360 19.069 69.456 ;
      RECT 0.216 70.128 19.069 70.224 ;
      RECT 0.216 70.896 19.069 70.992 ;
      RECT 0.216 71.664 19.069 71.760 ;
      RECT 0.216 72.432 19.069 72.528 ;
      RECT 0.216 73.200 19.069 73.296 ;
      RECT 0.216 73.968 19.069 74.064 ;
      RECT 0.216 74.736 19.069 74.832 ;
      RECT 0.216 75.504 19.069 75.600 ;
      RECT 0.216 76.272 19.069 76.368 ;
      RECT 0.216 77.040 19.069 77.136 ;
      RECT 0.216 77.808 19.069 77.904 ;
      RECT 0.216 78.576 19.069 78.672 ;
      RECT 0.216 79.344 19.069 79.440 ;
      RECT 0.216 80.112 19.069 80.208 ;
      RECT 0.216 80.880 19.069 80.976 ;
      RECT 0.216 81.648 19.069 81.744 ;
      RECT 0.216 82.416 19.069 82.512 ;
      RECT 0.216 83.184 19.069 83.280 ;
      RECT 0.216 83.952 19.069 84.048 ;
      RECT 0.216 84.720 19.069 84.816 ;
      RECT 0.216 85.488 19.069 85.584 ;
      RECT 0.216 86.256 19.069 86.352 ;
      RECT 0.216 87.024 19.069 87.120 ;
      RECT 0.216 87.792 19.069 87.888 ;
      RECT 0.216 88.560 19.069 88.656 ;
      RECT 0.216 89.328 19.069 89.424 ;
      RECT 0.216 90.096 19.069 90.192 ;
      RECT 0.216 90.864 19.069 90.960 ;
    END
  END VDD
  OBS
    LAYER M1 ;
    RECT 0 0 19.285 91.066 ;
    LAYER M2 ;
    RECT 0 0 19.285 91.066 ;
    LAYER M3 ;
    RECT 0 0 19.285 91.066 ;
    LAYER M4 ;
    RECT 0 0 19.285 91.066 ;
  END
END fakeram_64x512_1r1w

END LIBRARY
